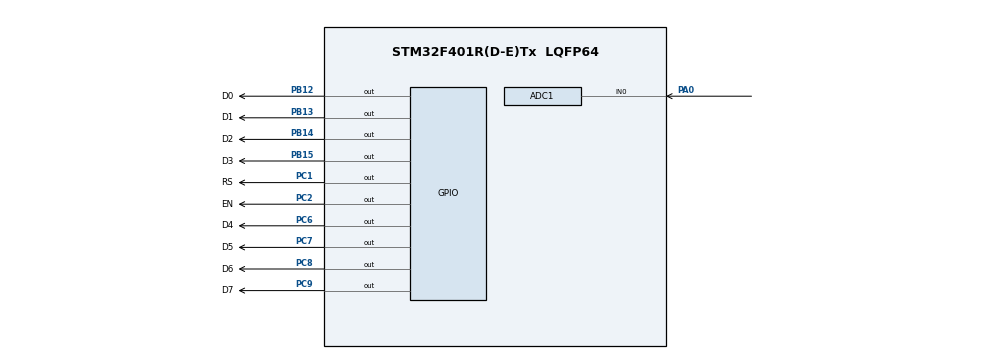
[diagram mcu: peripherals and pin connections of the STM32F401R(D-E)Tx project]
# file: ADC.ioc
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ADC1.Channel-7\#ChannelRegularConversion=ADC_CHANNEL_0
ADC1.ClockPrescaler=ADC_CLOCK_SYNC_PCLK_DIV8
ADC1.ContinuousConvMode=ENABLE
ADC1.NbrOfConversionFlag=1
ADC1.Rank-7\#ChannelRegularConversion=1
ADC1.Resolution=ADC_RESOLUTION_8B
ADC1.SamplingTime-7\#ChannelRegularConversion=ADC_SAMPLETIME_480CYCLES
ADC1.master=1
Mcu.Family=STM32F4
Mcu.Name=STM32F401R(D-E)Tx
Mcu.Package=LQFP64
NVIC.PriorityGroup=NVIC_PRIORITYGROUP_4
PA0-WKUP.Signal=ADCx_IN0
PB12.GPIO_Label=D0
PB12.Signal=GPIO_Output
PB13.GPIO_Label=D1
PB13.Signal=GPIO_Output
PB14.GPIO_Label=D2
PB14.Signal=GPIO_Output
PB15.GPIO_Label=D3
PB15.Signal=GPIO_Output
PC1.GPIO_Label=RS
PC1.Signal=GPIO_Output
PC2.GPIO_Label=EN
PC2.Signal=GPIO_Output
PC6.GPIO_Label=D4
PC6.Signal=GPIO_Output
PC7.GPIO_Label=D5
PC7.Signal=GPIO_Output
PC8.GPIO_Label=D6
PC8.Signal=GPIO_Output
PC9.GPIO_Label=D7
PC9.Signal=GPIO_Output
ProjectManager.HeapSize=0x200
ProjectManager.StackSize=0x400
ProjectManager.TargetToolchain=STM32CubeIDE
RCC.48MHZClocksFreq_Value=32000000
RCC.AHBCLKDivider=RCC_SYSCLK_DIV4
RCC.AHBFreq_Value=16000000
RCC.APB1Freq_Value=16000000
RCC.APB1TimFreq_Value=16000000
RCC.APB2Freq_Value=16000000
RCC.APB2TimFreq_Value=16000000
RCC.CortexFreq_Value=16000000
RCC.HCLKFreq_Value=16000000
RCC.HSE_VALUE=25000000
RCC.HSI_VALUE=16000000
RCC.LSE_VALUE=32768
RCC.PLLM=8
RCC.PLLN=64
RCC.SYSCLKFreq_VALUE=64000000
RCC.SYSCLKSource=RCC_SYSCLKSOURCE_PLLCLK
RCC.VCOOutputFreq_Value=128000000
SH.ADCx_IN0.0=ADC1_IN0,IN0
board=custom

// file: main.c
/* USER CODE BEGIN Header */
/**
  ******************************************************************************
  * @file           : main.c
  * @brief          : Main program body
  ******************************************************************************
  * @attention
  *
  * <h2><center>&copy; Copyright (c) 2020 STMicroelectronics.
  * All rights reserved.</center></h2>
  *
  * This software component is licensed by ST under BSD 3-Clause license,
  * the "License"; You may not use this file except in compliance with the
  * License. You may obtain a copy of the License at:
  *                        opensource.org/licenses/BSD-3-Clause
  *
  ******************************************************************************
  */
/* USER CODE END Header */

#include "main.h"

/* USER CODE BEGIN Includes */
#include "STM_MY_LCD16X2.h"

/* USER CODE END Includes */

ADC_HandleTypeDef hadc1;

void SystemClock_Config(void);
static void MX_GPIO_Init(void);
static void MX_ADC1_Init(void);

int main(void)
{
  /* USER CODE BEGIN 1 */
	uint32_t adc_value = 0;
	float real_value;

  /* USER CODE END 1 */

  /* MCU Configuration--------------------------------------------------------*/

  /* Reset of all peripherals, Initializes the Flash interface and the Systick. */
  HAL_Init();

  /* Configure the system clock */
  SystemClock_Config();

  /* Initialize all configured peripherals */
  MX_GPIO_Init();
  MX_ADC1_Init();
  /* USER CODE BEGIN 2 */
  HAL_ADC_Start(&hadc1);
  LCD1602_Begin8BIT(GPIOC,GPIO_PIN_1,GPIO_PIN_2,GPIOB,GPIO_PIN_12,GPIO_PIN_13,GPIO_PIN_14,GPIO_PIN_15,GPIOC,GPIO_PIN_6,GPIO_PIN_7,GPIO_PIN_8,GPIO_PIN_9);

  /* USER CODE END 2 */

  /* Infinite loop */
  while (1)
  {

    /* USER CODE BEGIN 3 */
	  adc_value = HAL_ADC_GetValue(&hadc1);
	  real_value = (float)adc_value * 0.0008058608;
	  LCD1602_clear();
	  LCD1602_1stLine();
	  LCD1602_print("ADC:");
	  LCD1602_PrintInt(adc_value);
	  LCD1602_2ndLine();
	  LCD1602_print("Voltage:");
	  LCD1602_PrintFloat(real_value, 3);
	  HAL_Delay(50);
  }
  /* USER CODE END 3 */
}

void SystemClock_Config(void)
{
  RCC_OscInitTypeDef RCC_OscInitStruct = {0};
  RCC_ClkInitTypeDef RCC_ClkInitStruct = {0};

  /** Configure the main internal regulator output voltage
  */
  __HAL_RCC_PWR_CLK_ENABLE();
  __HAL_PWR_VOLTAGESCALING_CONFIG(PWR_REGULATOR_VOLTAGE_SCALE2);
  /** Initializes the CPU, AHB and APB busses clocks
  */
  RCC_OscInitStruct.OscillatorType = RCC_OSCILLATORTYPE_HSI;
  RCC_OscInitStruct.HSIState = RCC_HSI_ON;
  RCC_OscInitStruct.HSICalibrationValue = RCC_HSICALIBRATION_DEFAULT;
  RCC_OscInitStruct.PLL.PLLState = RCC_PLL_ON;
  RCC_OscInitStruct.PLL.PLLSource = RCC_PLLSOURCE_HSI;
  RCC_OscInitStruct.PLL.PLLM = 8;
  RCC_OscInitStruct.PLL.PLLN = 64;
  RCC_OscInitStruct.PLL.PLLP = RCC_PLLP_DIV2;
  RCC_OscInitStruct.PLL.PLLQ = 4;
  if (HAL_RCC_OscConfig(&RCC_OscInitStruct) != HAL_OK)
  {
    Error_Handler();
  }
  /** Initializes the CPU, AHB and APB busses clocks
  */
  RCC_ClkInitStruct.ClockType = RCC_CLOCKTYPE_HCLK|RCC_CLOCKTYPE_SYSCLK
                              |RCC_CLOCKTYPE_PCLK1|RCC_CLOCKTYPE_PCLK2;
  RCC_ClkInitStruct.SYSCLKSource = RCC_SYSCLKSOURCE_PLLCLK;
  RCC_ClkInitStruct.AHBCLKDivider = RCC_SYSCLK_DIV4;
  RCC_ClkInitStruct.APB1CLKDivider = RCC_HCLK_DIV2;
  RCC_ClkInitStruct.APB2CLKDivider = RCC_HCLK_DIV1;

  if (HAL_RCC_ClockConfig(&RCC_ClkInitStruct, FLASH_LATENCY_0) != HAL_OK)
  {
    Error_Handler();
  }
}

static void MX_ADC1_Init(void)
{

  ADC_ChannelConfTypeDef sConfig = {0};

  /** Configure the global features of the ADC (Clock, Resolution, Data Alignment and number of conversion)
  */
  hadc1.Instance = ADC1;
  hadc1.Init.ClockPrescaler = ADC_CLOCK_SYNC_PCLK_DIV8;
  hadc1.Init.Resolution = ADC_RESOLUTION_8B;
  hadc1.Init.ScanConvMode = DISABLE;
  hadc1.Init.ContinuousConvMode = ENABLE;
  hadc1.Init.DiscontinuousConvMode = DISABLE;
  hadc1.Init.ExternalTrigConvEdge = ADC_EXTERNALTRIGCONVEDGE_NONE;
  hadc1.Init.ExternalTrigConv = ADC_SOFTWARE_START;
  hadc1.Init.DataAlign = ADC_DATAALIGN_RIGHT;
  hadc1.Init.NbrOfConversion = 1;
  hadc1.Init.DMAContinuousRequests = DISABLE;
  hadc1.Init.EOCSelection = ADC_EOC_SINGLE_CONV;
  if (HAL_ADC_Init(&hadc1) != HAL_OK)
  {
    Error_Handler();
  }
  /** Configure for the selected ADC regular channel its corresponding rank in the sequencer and its sample time.
  */
  sConfig.Channel = ADC_CHANNEL_0;
  sConfig.Rank = 1;
  sConfig.SamplingTime = ADC_SAMPLETIME_480CYCLES;
  if (HAL_ADC_ConfigChannel(&hadc1, &sConfig) != HAL_OK)
  {
    Error_Handler();
  }

}

static void MX_GPIO_Init(void)
{
  GPIO_InitTypeDef GPIO_InitStruct = {0};

  /* GPIO Ports Clock Enable */
  __HAL_RCC_GPIOC_CLK_ENABLE();
  __HAL_RCC_GPIOA_CLK_ENABLE();
  __HAL_RCC_GPIOB_CLK_ENABLE();

  /*Configure GPIO pin Output Level */
  HAL_GPIO_WritePin(GPIOC, RS_Pin|EN_Pin|D4_Pin|D5_Pin
                          |D6_Pin|D7_Pin, GPIO_PIN_RESET);

  /*Configure GPIO pin Output Level */
  HAL_GPIO_WritePin(GPIOB, D0_Pin|D1_Pin|D2_Pin|D3_Pin, GPIO_PIN_RESET);

  /*Configure GPIO pins : RS_Pin EN_Pin D4_Pin D5_Pin
                           D6_Pin D7_Pin */
  GPIO_InitStruct.Pin = RS_Pin|EN_Pin|D4_Pin|D5_Pin
                          |D6_Pin|D7_Pin;
  GPIO_InitStruct.Mode = GPIO_MODE_OUTPUT_PP;
  GPIO_InitStruct.Pull = GPIO_NOPULL;
  GPIO_InitStruct.Speed = GPIO_SPEED_FREQ_LOW;
  HAL_GPIO_Init(GPIOC, &GPIO_InitStruct);

  /*Configure GPIO pins : D0_Pin D1_Pin D2_Pin D3_Pin */
  GPIO_InitStruct.Pin = D0_Pin|D1_Pin|D2_Pin|D3_Pin;
  GPIO_InitStruct.Mode = GPIO_MODE_OUTPUT_PP;
  GPIO_InitStruct.Pull = GPIO_NOPULL;
  GPIO_InitStruct.Speed = GPIO_SPEED_FREQ_LOW;
  HAL_GPIO_Init(GPIOB, &GPIO_InitStruct);

}

void Error_Handler(void)
{
}

/************************ (C) COPYRIGHT STMicroelectronics *****END OF FILE****/
